VERSION 5.8 ;
BUSBITCHARS "[]" ;
DIVIDERCHAR "/" ;
UNITS
    DATABASE MICRONS 1000 ;
END UNITS

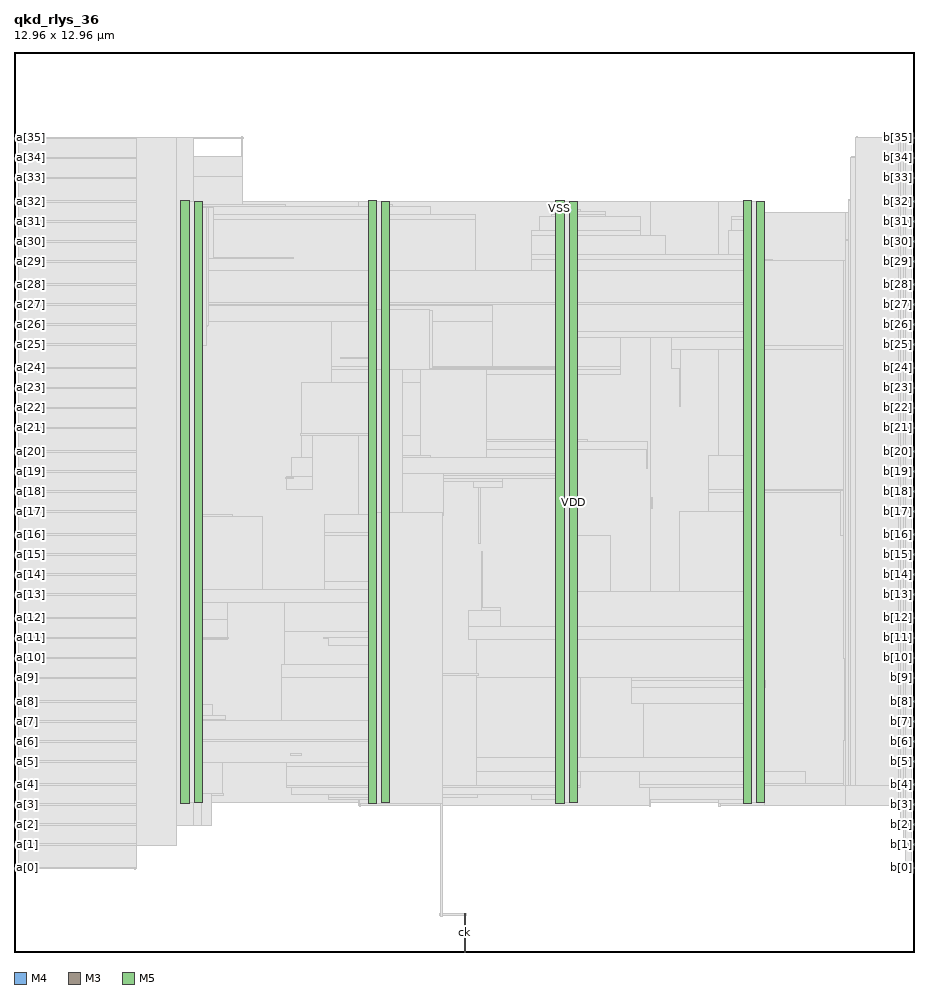
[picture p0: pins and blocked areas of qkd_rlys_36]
MACRO qkd_rlys_36
  FOREIGN qkd_rlys_36 0 0 ;
  CLASS BLOCK ;
  SIZE 12.96 BY 12.96 ;
  PIN a[0]
    DIRECTION INPUT ;
    USE SIGNAL ;
    PORT
      LAYER M4 ;
        RECT  0 1.2 0.084 1.224 ;
    END
  END a[0]
  PIN a[10]
    DIRECTION INPUT ;
    USE SIGNAL ;
    PORT
      LAYER M4 ;
        RECT  0 4.224 0.084 4.248 ;
    END
  END a[10]
  PIN a[11]
    DIRECTION INPUT ;
    USE SIGNAL ;
    PORT
      LAYER M4 ;
        RECT  0 4.512 0.084 4.536 ;
    END
  END a[11]
  PIN a[12]
    DIRECTION INPUT ;
    USE SIGNAL ;
    PORT
      LAYER M4 ;
        RECT  0 4.8 0.084 4.824 ;
    END
  END a[12]
  PIN a[13]
    DIRECTION INPUT ;
    USE SIGNAL ;
    PORT
      LAYER M4 ;
        RECT  0 5.136 0.084 5.16 ;
    END
  END a[13]
  PIN a[14]
    DIRECTION INPUT ;
    USE SIGNAL ;
    PORT
      LAYER M4 ;
        RECT  0 5.424 0.084 5.448 ;
    END
  END a[14]
  PIN a[15]
    DIRECTION INPUT ;
    USE SIGNAL ;
    PORT
      LAYER M4 ;
        RECT  0 5.712 0.084 5.736 ;
    END
  END a[15]
  PIN a[16]
    DIRECTION INPUT ;
    USE SIGNAL ;
    PORT
      LAYER M4 ;
        RECT  0 6 0.084 6.024 ;
    END
  END a[16]
  PIN a[17]
    DIRECTION INPUT ;
    USE SIGNAL ;
    PORT
      LAYER M4 ;
        RECT  0 6.336 0.084 6.36 ;
    END
  END a[17]
  PIN a[18]
    DIRECTION INPUT ;
    USE SIGNAL ;
    PORT
      LAYER M4 ;
        RECT  0 6.624 0.084 6.648 ;
    END
  END a[18]
  PIN a[19]
    DIRECTION INPUT ;
    USE SIGNAL ;
    PORT
      LAYER M4 ;
        RECT  0 6.912 0.084 6.936 ;
    END
  END a[19]
  PIN a[1]
    DIRECTION INPUT ;
    USE SIGNAL ;
    PORT
      LAYER M4 ;
        RECT  0 1.536 0.084 1.56 ;
    END
  END a[1]
  PIN a[20]
    DIRECTION INPUT ;
    USE SIGNAL ;
    PORT
      LAYER M4 ;
        RECT  0 7.2 0.084 7.224 ;
    END
  END a[20]
  PIN a[21]
    DIRECTION INPUT ;
    USE SIGNAL ;
    PORT
      LAYER M4 ;
        RECT  0 7.536 0.084 7.56 ;
    END
  END a[21]
  PIN a[22]
    DIRECTION INPUT ;
    USE SIGNAL ;
    PORT
      LAYER M4 ;
        RECT  0 7.824 0.084 7.848 ;
    END
  END a[22]
  PIN a[23]
    DIRECTION INPUT ;
    USE SIGNAL ;
    PORT
      LAYER M4 ;
        RECT  0 8.112 0.084 8.136 ;
    END
  END a[23]
  PIN a[24]
    DIRECTION INPUT ;
    USE SIGNAL ;
    PORT
      LAYER M4 ;
        RECT  0 8.4 0.084 8.424 ;
    END
  END a[24]
  PIN a[25]
    DIRECTION INPUT ;
    USE SIGNAL ;
    PORT
      LAYER M4 ;
        RECT  0 8.736 0.084 8.76 ;
    END
  END a[25]
  PIN a[26]
    DIRECTION INPUT ;
    USE SIGNAL ;
    PORT
      LAYER M4 ;
        RECT  0 9.024 0.084 9.048 ;
    END
  END a[26]
  PIN a[27]
    DIRECTION INPUT ;
    USE SIGNAL ;
    PORT
      LAYER M4 ;
        RECT  0 9.312 0.084 9.336 ;
    END
  END a[27]
  PIN a[28]
    DIRECTION INPUT ;
    USE SIGNAL ;
    PORT
      LAYER M4 ;
        RECT  0 9.6 0.084 9.624 ;
    END
  END a[28]
  PIN a[29]
    DIRECTION INPUT ;
    USE SIGNAL ;
    PORT
      LAYER M4 ;
        RECT  0 9.936 0.084 9.96 ;
    END
  END a[29]
  PIN a[2]
    DIRECTION INPUT ;
    USE SIGNAL ;
    PORT
      LAYER M4 ;
        RECT  0 1.824 0.084 1.848 ;
    END
  END a[2]
  PIN a[30]
    DIRECTION INPUT ;
    USE SIGNAL ;
    PORT
      LAYER M4 ;
        RECT  0 10.224 0.084 10.248 ;
    END
  END a[30]
  PIN a[31]
    DIRECTION INPUT ;
    USE SIGNAL ;
    PORT
      LAYER M4 ;
        RECT  0 10.512 0.084 10.536 ;
    END
  END a[31]
  PIN a[32]
    DIRECTION INPUT ;
    USE SIGNAL ;
    PORT
      LAYER M4 ;
        RECT  0 10.8 0.084 10.824 ;
    END
  END a[32]
  PIN a[33]
    DIRECTION INPUT ;
    USE SIGNAL ;
    PORT
      LAYER M4 ;
        RECT  0 11.136 0.084 11.16 ;
    END
  END a[33]
  PIN a[34]
    DIRECTION INPUT ;
    USE SIGNAL ;
    PORT
      LAYER M4 ;
        RECT  0 11.424 0.084 11.448 ;
    END
  END a[34]
  PIN a[35]
    DIRECTION INPUT ;
    USE SIGNAL ;
    PORT
      LAYER M4 ;
        RECT  0 11.712 0.084 11.736 ;
    END
  END a[35]
  PIN a[3]
    DIRECTION INPUT ;
    USE SIGNAL ;
    PORT
      LAYER M4 ;
        RECT  0 2.112 0.084 2.136 ;
    END
  END a[3]
  PIN a[4]
    DIRECTION INPUT ;
    USE SIGNAL ;
    PORT
      LAYER M4 ;
        RECT  0 2.4 0.084 2.424 ;
    END
  END a[4]
  PIN a[5]
    DIRECTION INPUT ;
    USE SIGNAL ;
    PORT
      LAYER M4 ;
        RECT  0 2.736 0.084 2.76 ;
    END
  END a[5]
  PIN a[6]
    DIRECTION INPUT ;
    USE SIGNAL ;
    PORT
      LAYER M4 ;
        RECT  0 3.024 0.084 3.048 ;
    END
  END a[6]
  PIN a[7]
    DIRECTION INPUT ;
    USE SIGNAL ;
    PORT
      LAYER M4 ;
        RECT  0 3.312 0.084 3.336 ;
    END
  END a[7]
  PIN a[8]
    DIRECTION INPUT ;
    USE SIGNAL ;
    PORT
      LAYER M4 ;
        RECT  0 3.6 0.084 3.624 ;
    END
  END a[8]
  PIN a[9]
    DIRECTION INPUT ;
    USE SIGNAL ;
    PORT
      LAYER M4 ;
        RECT  0 3.936 0.084 3.96 ;
    END
  END a[9]
  PIN b[0]
    DIRECTION OUTPUT ;
    USE SIGNAL ;
    PORT
      LAYER M4 ;
        RECT  12.876 1.2 12.96 1.224 ;
    END
  END b[0]
  PIN b[10]
    DIRECTION OUTPUT ;
    USE SIGNAL ;
    PORT
      LAYER M4 ;
        RECT  12.876 4.224 12.96 4.248 ;
    END
  END b[10]
  PIN b[11]
    DIRECTION OUTPUT ;
    USE SIGNAL ;
    PORT
      LAYER M4 ;
        RECT  12.876 4.512 12.96 4.536 ;
    END
  END b[11]
  PIN b[12]
    DIRECTION OUTPUT ;
    USE SIGNAL ;
    PORT
      LAYER M4 ;
        RECT  12.876 4.8 12.96 4.824 ;
    END
  END b[12]
  PIN b[13]
    DIRECTION OUTPUT ;
    USE SIGNAL ;
    PORT
      LAYER M4 ;
        RECT  12.876 5.136 12.96 5.16 ;
    END
  END b[13]
  PIN b[14]
    DIRECTION OUTPUT ;
    USE SIGNAL ;
    PORT
      LAYER M4 ;
        RECT  12.876 5.424 12.96 5.448 ;
    END
  END b[14]
  PIN b[15]
    DIRECTION OUTPUT ;
    USE SIGNAL ;
    PORT
      LAYER M4 ;
        RECT  12.876 5.712 12.96 5.736 ;
    END
  END b[15]
  PIN b[16]
    DIRECTION OUTPUT ;
    USE SIGNAL ;
    PORT
      LAYER M4 ;
        RECT  12.876 6 12.96 6.024 ;
    END
  END b[16]
  PIN b[17]
    DIRECTION OUTPUT ;
    USE SIGNAL ;
    PORT
      LAYER M4 ;
        RECT  12.876 6.336 12.96 6.36 ;
    END
  END b[17]
  PIN b[18]
    DIRECTION OUTPUT ;
    USE SIGNAL ;
    PORT
      LAYER M4 ;
        RECT  12.876 6.624 12.96 6.648 ;
    END
  END b[18]
  PIN b[19]
    DIRECTION OUTPUT ;
    USE SIGNAL ;
    PORT
      LAYER M4 ;
        RECT  12.876 6.912 12.96 6.936 ;
    END
  END b[19]
  PIN b[1]
    DIRECTION OUTPUT ;
    USE SIGNAL ;
    PORT
      LAYER M4 ;
        RECT  12.876 1.536 12.96 1.56 ;
    END
  END b[1]
  PIN b[20]
    DIRECTION OUTPUT ;
    USE SIGNAL ;
    PORT
      LAYER M4 ;
        RECT  12.876 7.2 12.96 7.224 ;
    END
  END b[20]
  PIN b[21]
    DIRECTION OUTPUT ;
    USE SIGNAL ;
    PORT
      LAYER M4 ;
        RECT  12.876 7.536 12.96 7.56 ;
    END
  END b[21]
  PIN b[22]
    DIRECTION OUTPUT ;
    USE SIGNAL ;
    PORT
      LAYER M4 ;
        RECT  12.876 7.824 12.96 7.848 ;
    END
  END b[22]
  PIN b[23]
    DIRECTION OUTPUT ;
    USE SIGNAL ;
    PORT
      LAYER M4 ;
        RECT  12.876 8.112 12.96 8.136 ;
    END
  END b[23]
  PIN b[24]
    DIRECTION OUTPUT ;
    USE SIGNAL ;
    PORT
      LAYER M4 ;
        RECT  12.876 8.4 12.96 8.424 ;
    END
  END b[24]
  PIN b[25]
    DIRECTION OUTPUT ;
    USE SIGNAL ;
    PORT
      LAYER M4 ;
        RECT  12.876 8.736 12.96 8.76 ;
    END
  END b[25]
  PIN b[26]
    DIRECTION OUTPUT ;
    USE SIGNAL ;
    PORT
      LAYER M4 ;
        RECT  12.876 9.024 12.96 9.048 ;
    END
  END b[26]
  PIN b[27]
    DIRECTION OUTPUT ;
    USE SIGNAL ;
    PORT
      LAYER M4 ;
        RECT  12.876 9.312 12.96 9.336 ;
    END
  END b[27]
  PIN b[28]
    DIRECTION OUTPUT ;
    USE SIGNAL ;
    PORT
      LAYER M4 ;
        RECT  12.876 9.6 12.96 9.624 ;
    END
  END b[28]
  PIN b[29]
    DIRECTION OUTPUT ;
    USE SIGNAL ;
    PORT
      LAYER M4 ;
        RECT  12.876 9.936 12.96 9.96 ;
    END
  END b[29]
  PIN b[2]
    DIRECTION OUTPUT ;
    USE SIGNAL ;
    PORT
      LAYER M4 ;
        RECT  12.876 1.824 12.96 1.848 ;
    END
  END b[2]
  PIN b[30]
    DIRECTION OUTPUT ;
    USE SIGNAL ;
    PORT
      LAYER M4 ;
        RECT  12.876 10.224 12.96 10.248 ;
    END
  END b[30]
  PIN b[31]
    DIRECTION OUTPUT ;
    USE SIGNAL ;
    PORT
      LAYER M4 ;
        RECT  12.876 10.512 12.96 10.536 ;
    END
  END b[31]
  PIN b[32]
    DIRECTION OUTPUT ;
    USE SIGNAL ;
    PORT
      LAYER M4 ;
        RECT  12.876 10.8 12.96 10.824 ;
    END
  END b[32]
  PIN b[33]
    DIRECTION OUTPUT ;
    USE SIGNAL ;
    PORT
      LAYER M4 ;
        RECT  12.876 11.136 12.96 11.16 ;
    END
  END b[33]
  PIN b[34]
    DIRECTION OUTPUT ;
    USE SIGNAL ;
    PORT
      LAYER M4 ;
        RECT  12.876 11.424 12.96 11.448 ;
    END
  END b[34]
  PIN b[35]
    DIRECTION OUTPUT ;
    USE SIGNAL ;
    PORT
      LAYER M4 ;
        RECT  12.876 11.712 12.96 11.736 ;
    END
  END b[35]
  PIN b[3]
    DIRECTION OUTPUT ;
    USE SIGNAL ;
    PORT
      LAYER M4 ;
        RECT  12.876 2.112 12.96 2.136 ;
    END
  END b[3]
  PIN b[4]
    DIRECTION OUTPUT ;
    USE SIGNAL ;
    PORT
      LAYER M4 ;
        RECT  12.876 2.4 12.96 2.424 ;
    END
  END b[4]
  PIN b[5]
    DIRECTION OUTPUT ;
    USE SIGNAL ;
    PORT
      LAYER M4 ;
        RECT  12.876 2.736 12.96 2.76 ;
    END
  END b[5]
  PIN b[6]
    DIRECTION OUTPUT ;
    USE SIGNAL ;
    PORT
      LAYER M4 ;
        RECT  12.876 3.024 12.96 3.048 ;
    END
  END b[6]
  PIN b[7]
    DIRECTION OUTPUT ;
    USE SIGNAL ;
    PORT
      LAYER M4 ;
        RECT  12.876 3.312 12.96 3.336 ;
    END
  END b[7]
  PIN b[8]
    DIRECTION OUTPUT ;
    USE SIGNAL ;
    PORT
      LAYER M4 ;
        RECT  12.876 3.6 12.96 3.624 ;
    END
  END b[8]
  PIN b[9]
    DIRECTION OUTPUT ;
    USE SIGNAL ;
    PORT
      LAYER M4 ;
        RECT  12.876 3.936 12.96 3.96 ;
    END
  END b[9]
  PIN ck
    DIRECTION INPUT ;
    USE SIGNAL ;
    PORT
      LAYER M3 ;
        RECT  6.48 0 6.498 0.038 ;
    END
    PORT
      LAYER M3 ;
        RECT  6.48 0.012 6.498 0.557 ;
    END
  END ck
  PIN VDD
    DIRECTION INOUT ;
    USE POWER ;
    PORT
      LAYER M5 ;
        RECT  10.692 2.151 10.812 10.809 ;
        RECT  7.992 2.151 8.112 10.809 ;
        RECT  5.292 2.151 5.412 10.809 ;
        RECT  2.592 2.151 2.712 10.809 ;
    END
  END VDD
  PIN VSS
    DIRECTION INOUT ;
    USE GROUND ;
    PORT
      LAYER M5 ;
        RECT  10.5 2.137 10.62 10.823 ;
        RECT  7.8 2.137 7.92 10.823 ;
        RECT  5.1 2.137 5.22 10.823 ;
        RECT  2.4 2.137 2.52 10.823 ;
    END
  END VSS
  # OT_OBS_CLOSED layer=M5 d_um=1.536 added=0
  OBS
    LAYER RVTN ;
     RECT  2.16 2.16 10.8 2.295 ;
     RECT  2.16 2.565 10.8 2.835 ;
     RECT  2.16 3.105 10.8 3.375 ;
     RECT  2.16 3.645 10.8 3.915 ;
     RECT  2.16 4.185 10.8 4.455 ;
     RECT  2.16 4.725 10.8 4.995 ;
     RECT  2.16 5.265 10.8 5.535 ;
     RECT  2.16 5.805 10.8 6.075 ;
     RECT  2.16 6.345 10.8 6.615 ;
     RECT  2.16 6.885 10.8 7.155 ;
     RECT  2.16 7.425 10.8 7.695 ;
     RECT  2.16 7.965 10.8 8.235 ;
     RECT  2.16 8.505 10.8 8.775 ;
     RECT  2.16 9.045 10.8 9.315 ;
     RECT  2.16 9.585 10.8 9.855 ;
     RECT  2.16 10.125 10.8 10.395 ;
     RECT  2.16 10.665 10.8 10.8 ;
    LAYER RVTP ;
     RECT  2.16 2.295 10.8 2.565 ;
     RECT  2.16 2.835 10.8 3.105 ;
     RECT  2.16 3.375 10.8 3.645 ;
     RECT  2.16 3.915 10.8 4.185 ;
     RECT  2.16 4.455 10.8 4.725 ;
     RECT  2.16 4.995 10.8 5.265 ;
     RECT  2.16 5.535 10.8 5.805 ;
     RECT  2.16 6.075 10.8 6.345 ;
     RECT  2.16 6.615 10.8 6.885 ;
     RECT  2.16 7.155 10.8 7.425 ;
     RECT  2.16 7.695 10.8 7.965 ;
     RECT  2.16 8.235 10.8 8.505 ;
     RECT  2.16 8.775 10.8 9.045 ;
     RECT  2.16 9.315 10.8 9.585 ;
     RECT  2.16 9.855 10.8 10.125 ;
     RECT  2.16 10.395 10.8 10.665 ;
    LAYER M1 ;
     RECT  2.16 2.151 10.8 10.809 ;
    LAYER M2 ;
     RECT  1.723 2.232 2.16 2.25 ;
     RECT  2.16 2.151 4.963 10.809 ;
     RECT  4.963 2.106 9.167 10.809 ;
     RECT  9.167 2.151 10.147 10.809 ;
     RECT  10.147 2.106 10.8 10.809 ;
     RECT  10.8 2.106 11.975 10.656 ;
     RECT  11.975 5.004 12.011 5.022 ;
     RECT  11.975 6.156 12.011 6.804 ;
     RECT  11.975 8.946 12.011 10.656 ;
     RECT  12.011 9.63 12.119 10.656 ;
     RECT  12.119 9.63 12.155 9.648 ;
     RECT  11.975 2.106 12.803 4.014 ;
     RECT  12.803 3.186 12.839 4.014 ;
     RECT  12.803 2.106 12.875 2.124 ;
     RECT  12.839 3.42 12.875 4.014 ;
     RECT  12.119 10.638 12.875 10.656 ;
    LAYER M3 ;
     RECT  1.728 1.195 1.746 1.531 ;
     RECT  12.852 1.195 12.87 1.531 ;
     RECT  1.728 1.531 2.322 1.819 ;
     RECT  12.816 1.531 12.87 1.819 ;
     RECT  12.78 1.819 12.87 2.107 ;
     RECT  4.968 2.101 4.986 2.143 ;
     RECT  10.152 2.101 10.17 2.143 ;
     RECT  4.968 2.143 5.205 2.191 ;
     RECT  7.815 2.143 7.905 2.191 ;
     RECT  9.144 2.101 9.162 2.191 ;
     RECT  10.152 2.143 10.605 2.191 ;
     RECT  4.536 2.191 6.03 2.227 ;
     RECT  1.728 1.819 2.826 2.251 ;
     RECT  1.728 2.251 3.006 2.255 ;
     RECT  4.536 2.227 6.678 2.263 ;
     RECT  7.452 2.191 7.905 2.263 ;
     RECT  0.108 2.107 0.126 2.285 ;
     RECT  3.996 2.263 7.905 2.371 ;
     RECT  9.144 2.191 10.605 2.371 ;
     RECT  3.924 2.371 8.154 2.399 ;
     RECT  12.744 2.107 12.87 2.399 ;
     RECT  9 2.371 10.605 2.413 ;
     RECT  11.376 2.395 11.394 2.413 ;
     RECT  9 2.413 11.394 2.597 ;
     RECT  6.66 2.399 8.154 2.605 ;
     RECT  9 2.597 10.797 2.605 ;
     RECT  3.924 2.399 5.742 2.669 ;
     RECT  12.78 2.399 12.87 2.669 ;
     RECT  2.304 2.255 3.006 2.731 ;
     RECT  3.924 2.669 5.562 2.731 ;
     RECT  6.66 2.605 10.797 2.795 ;
     RECT  2.304 2.731 5.562 3.029 ;
     RECT  2.304 3.029 5.454 3.065 ;
     RECT  2.304 3.065 5.397 3.335 ;
     RECT  2.304 3.335 3.042 3.344 ;
     RECT  2.34 3.344 3.042 3.407 ;
     RECT  11.952 3.019 11.97 3.451 ;
     RECT  2.34 3.407 2.862 3.569 ;
     RECT  9.072 2.795 10.797 3.577 ;
     RECT  11.952 3.451 12.006 3.629 ;
     RECT  8.892 3.577 10.797 3.811 ;
     RECT  12.816 2.669 12.87 3.839 ;
     RECT  8.892 3.811 10.818 3.911 ;
     RECT  3.852 3.335 5.397 3.955 ;
     RECT  6.66 2.795 8.154 3.955 ;
     RECT  8.892 3.911 10.797 3.955 ;
     RECT  12.852 3.839 12.87 4.019 ;
     RECT  3.852 3.955 5.742 4.145 ;
     RECT  6.66 3.955 10.797 4.495 ;
     RECT  2.34 3.569 2.697 4.507 ;
     RECT  3.888 4.145 5.742 4.621 ;
     RECT  6.552 4.495 10.797 4.685 ;
     RECT  2.34 4.507 3.078 4.795 ;
     RECT  6.552 4.685 7.002 4.919 ;
     RECT  6.732 4.919 7.002 4.955 ;
     RECT  11.952 3.629 11.97 4.999 ;
     RECT  2.304 4.795 3.078 5.035 ;
     RECT  3.888 4.621 5.778 5.035 ;
     RECT  11.952 4.999 12.006 5.165 ;
     RECT  7.815 4.685 10.797 5.189 ;
     RECT  2.304 5.035 5.778 5.225 ;
     RECT  4.464 5.225 5.778 5.341 ;
     RECT  6.732 4.955 6.75 5.765 ;
     RECT  11.952 5.165 11.97 5.995 ;
     RECT  4.464 5.341 5.922 5.999 ;
     RECT  7.815 5.189 8.586 5.999 ;
     RECT  4.464 5.999 5.706 6.035 ;
     RECT  11.916 5.995 11.97 6.151 ;
     RECT  2.304 5.225 3.582 6.269 ;
     RECT  2.304 6.269 3.15 6.305 ;
     RECT  4.464 6.035 5.418 6.305 ;
     RECT  9.576 5.189 10.797 6.341 ;
     RECT  9.18 6.385 9.198 6.539 ;
     RECT  10.008 6.341 10.797 6.613 ;
     RECT  11.916 6.151 12.006 6.613 ;
     RECT  10.008 6.613 12.006 6.653 ;
     RECT  6.696 5.881 6.714 6.691 ;
     RECT  5.115 6.305 5.418 6.781 ;
     RECT  6.624 6.691 7.038 6.781 ;
     RECT  5.115 6.781 7.038 6.817 ;
     RECT  7.815 5.999 8.097 6.817 ;
     RECT  3.924 6.655 4.302 6.845 ;
     RECT  11.952 6.653 12.006 6.941 ;
     RECT  3.996 6.845 4.302 7.115 ;
     RECT  5.115 6.817 8.097 7.115 ;
     RECT  5.115 7.115 5.994 7.151 ;
     RECT  10.008 6.653 10.797 7.151 ;
     RECT  6.804 7.115 8.097 7.231 ;
     RECT  9.108 6.961 9.126 7.231 ;
     RECT  6.804 7.231 9.126 7.349 ;
     RECT  6.804 7.349 8.262 7.385 ;
     RECT  4.14 7.115 4.302 7.435 ;
     RECT  5.115 7.151 5.85 7.435 ;
     RECT  2.304 6.305 2.697 8.195 ;
     RECT  4.14 7.435 5.85 8.195 ;
     RECT  6.804 7.385 8.097 8.311 ;
     RECT  4.572 8.195 5.85 8.395 ;
     RECT  6.804 8.311 8.73 8.395 ;
     RECT  9.576 7.861 9.594 8.401 ;
     RECT  4.572 8.395 8.73 8.429 ;
     RECT  9.468 8.401 9.594 8.671 ;
     RECT  10.515 7.151 10.797 8.671 ;
     RECT  11.952 6.941 11.97 8.671 ;
     RECT  2.415 8.195 2.697 8.731 ;
     RECT  7.815 8.429 8.73 8.851 ;
     RECT  9.468 8.671 11.97 8.851 ;
     RECT  7.815 8.851 11.97 8.941 ;
     RECT  2.415 8.731 2.754 9.004 ;
     RECT  2.415 9.004 2.79 9.085 ;
     RECT  4.572 8.429 6.894 9.085 ;
     RECT  2.415 9.085 6.894 9.307 ;
     RECT  2.304 9.307 6.894 9.319 ;
     RECT  7.815 8.941 12.006 9.319 ;
     RECT  2.304 9.319 12.006 9.347 ;
     RECT  11.988 9.347 12.006 9.625 ;
     RECT  2.304 9.347 10.926 9.815 ;
     RECT  7.452 9.815 10.926 9.965 ;
     RECT  7.452 9.965 10.797 10.049 ;
     RECT  11.988 9.625 12.15 10.253 ;
     RECT  7.452 10.049 9.378 10.319 ;
     RECT  7.452 10.319 9.018 10.391 ;
     RECT  10.296 10.049 10.797 10.391 ;
     RECT  12.024 10.253 12.15 10.507 ;
     RECT  2.304 9.815 6.642 10.541 ;
     RECT  10.332 10.391 10.797 10.547 ;
     RECT  7.56 10.391 9.018 10.589 ;
     RECT  10.332 10.547 10.605 10.589 ;
     RECT  2.34 10.541 6.642 10.625 ;
     RECT  7.74 10.589 8.514 10.625 ;
     RECT  7.815 10.625 8.514 10.661 ;
     RECT  12.024 10.507 12.87 10.661 ;
     RECT  7.815 10.661 8.154 10.697 ;
     RECT  2.34 10.625 5.994 10.733 ;
     RECT  2.34 10.733 3.906 10.769 ;
     RECT  5.115 10.733 5.454 10.769 ;
     RECT  5.115 10.769 5.205 10.817 ;
     RECT  7.815 10.697 7.905 10.817 ;
     RECT  10.515 10.589 10.605 10.817 ;
     RECT  0.108 10.699 0.126 10.829 ;
     RECT  12.024 10.661 12.15 10.829 ;
     RECT  2.34 10.769 3.294 11.165 ;
     RECT  2.556 11.165 3.294 11.453 ;
     RECT  12.06 10.829 12.15 11.453 ;
     RECT  3.276 11.453 3.294 11.741 ;
     RECT  12.132 11.453 12.15 11.741 ;
    LAYER M4 ;
     RECT  0.084 1.2 1.757 1.224 ;
     RECT  0.06 1.224 1.757 1.536 ;
     RECT  0.084 1.536 1.757 1.56 ;
     RECT  0.06 1.56 1.757 1.824 ;
     RECT  0.084 1.824 1.757 1.848 ;
     RECT  0.06 1.848 1.757 2.112 ;
     RECT  0.084 2.112 1.757 2.136 ;
     RECT  0.06 2.136 1.757 2.4 ;
     RECT  0.084 2.4 1.757 2.424 ;
     RECT  0.06 2.424 1.757 2.736 ;
     RECT  0.084 2.736 1.757 2.76 ;
     RECT  0.06 2.76 1.757 3.024 ;
     RECT  0.084 3.024 1.757 3.048 ;
     RECT  0.06 3.048 1.757 3.312 ;
     RECT  0.084 3.312 1.757 3.336 ;
     RECT  0.06 3.336 1.757 3.6 ;
     RECT  0.084 3.6 1.757 3.624 ;
     RECT  0.06 3.624 1.757 3.936 ;
     RECT  0.084 3.936 1.757 3.96 ;
     RECT  0.06 3.96 1.757 4.224 ;
     RECT  0.084 4.224 1.757 4.248 ;
     RECT  0.06 4.248 1.757 4.512 ;
     RECT  0.084 4.512 1.757 4.536 ;
     RECT  0.06 4.536 1.757 4.8 ;
     RECT  0.084 4.8 1.757 4.824 ;
     RECT  0.06 4.824 1.757 5.136 ;
     RECT  0.084 5.136 1.757 5.16 ;
     RECT  0.06 5.16 1.757 5.424 ;
     RECT  0.084 5.424 1.757 5.448 ;
     RECT  0.06 5.448 1.757 5.712 ;
     RECT  0.084 5.712 1.757 5.736 ;
     RECT  0.06 5.736 1.757 6 ;
     RECT  0.084 6 1.757 6.024 ;
     RECT  0.06 6.024 1.757 6.336 ;
     RECT  0.084 6.336 1.757 6.36 ;
     RECT  0.06 6.36 1.757 6.624 ;
     RECT  0.084 6.624 1.757 6.648 ;
     RECT  0.06 6.648 1.757 6.912 ;
     RECT  0.084 6.912 1.757 6.936 ;
     RECT  0.06 6.936 1.757 7.2 ;
     RECT  0.084 7.2 1.757 7.224 ;
     RECT  0.06 7.224 1.757 7.536 ;
     RECT  0.084 7.536 1.757 7.56 ;
     RECT  0.06 7.56 1.757 7.824 ;
     RECT  0.084 7.824 1.757 7.848 ;
     RECT  0.06 7.848 1.757 8.112 ;
     RECT  0.084 8.112 1.757 8.136 ;
     RECT  0.06 8.136 1.757 8.4 ;
     RECT  0.084 8.4 1.757 8.424 ;
     RECT  0.06 8.424 1.757 8.736 ;
     RECT  0.084 8.736 1.757 8.76 ;
     RECT  0.06 8.76 1.757 9.024 ;
     RECT  0.084 9.024 1.757 9.048 ;
     RECT  0.06 9.048 1.757 9.312 ;
     RECT  0.084 9.312 1.757 9.336 ;
     RECT  0.06 9.336 1.757 9.6 ;
     RECT  0.084 9.6 1.757 9.624 ;
     RECT  0.06 9.624 1.757 9.936 ;
     RECT  0.084 9.936 1.757 9.96 ;
     RECT  0.06 9.96 1.757 10.224 ;
     RECT  0.084 10.224 1.757 10.248 ;
     RECT  0.06 10.248 1.757 10.512 ;
     RECT  0.084 10.512 1.757 10.536 ;
     RECT  0.06 10.536 1.757 10.8 ;
     RECT  0.084 10.8 1.757 10.824 ;
     RECT  0.06 10.824 1.757 11.136 ;
     RECT  0.084 11.136 1.757 11.16 ;
     RECT  0.06 11.16 1.757 11.424 ;
     RECT  0.084 11.424 1.757 11.448 ;
     RECT  0.06 11.448 1.757 11.712 ;
     RECT  0.084 11.712 1.757 11.736 ;
     RECT  1.757 1.536 2.333 11.736 ;
     RECT  2.333 1.824 2.585 11.736 ;
     RECT  2.585 1.824 2.704 10.728 ;
     RECT  2.704 8.736 2.765 10.728 ;
     RECT  2.765 9.024 2.801 10.728 ;
     RECT  2.704 1.824 2.837 2.28 ;
     RECT  2.801 9.984 2.873 10.728 ;
     RECT  2.837 2.256 3.017 2.28 ;
     RECT  2.704 4.512 3.089 4.536 ;
     RECT  2.585 11.712 3.305 11.736 ;
     RECT  3.913 6.816 4.025 6.84 ;
     RECT  2.873 9.984 4.025 10.008 ;
     RECT  3.985 2.832 4.133 2.856 ;
     RECT  4.453 4.512 4.525 4.536 ;
     RECT  4.525 4.416 5.108 4.536 ;
     RECT  4.129 7.44 5.108 7.464 ;
     RECT  4.705 8.544 5.108 8.568 ;
     RECT  5.108 2.148 5.212 10.812 ;
     RECT  5.212 2.418 5.404 10.542 ;
     RECT  5.404 3.984 5.609 5.112 ;
     RECT  5.404 8.4 6.028 9.24 ;
     RECT  5.404 6.288 6.179 6.888 ;
     RECT  6.133 0.528 6.509 0.552 ;
     RECT  5.609 3.984 6.689 4.008 ;
     RECT  6.179 6.864 7.808 6.888 ;
     RECT  6.028 8.4 7.808 8.424 ;
     RECT  7.808 2.148 7.912 10.812 ;
     RECT  7.912 2.418 8.104 10.542 ;
     RECT  10.508 2.148 10.612 10.812 ;
     RECT  10.612 2.4 10.804 10.542 ;
     RECT  10.804 6.624 11.905 6.648 ;
     RECT  10.804 2.4 11.941 2.424 ;
     RECT  11.905 6 11.941 6.648 ;
     RECT  10.804 8.736 11.941 9.96 ;
     RECT  11.941 2.4 11.977 3.048 ;
     RECT  11.941 4.224 11.977 9.96 ;
     RECT  11.977 2.4 12.013 10.248 ;
     RECT  12.013 2.4 12.049 10.824 ;
     RECT  12.049 2.4 12.121 11.448 ;
     RECT  12.121 2.4 12.733 11.736 ;
     RECT  12.733 2.112 12.769 11.736 ;
     RECT  12.769 1.824 12.805 11.736 ;
     RECT  12.805 1.536 12.841 11.736 ;
     RECT  12.841 1.2 12.876 1.224 ;
     RECT  12.841 1.224 12.924 1.536 ;
     RECT  12.841 1.536 12.876 1.56 ;
     RECT  12.841 1.56 12.924 1.824 ;
     RECT  12.841 1.824 12.876 1.848 ;
     RECT  12.841 1.848 12.924 2.112 ;
     RECT  12.841 2.112 12.876 2.136 ;
     RECT  12.841 2.136 12.924 2.4 ;
     RECT  12.841 2.4 12.876 2.424 ;
     RECT  12.841 2.424 12.924 2.736 ;
     RECT  12.841 2.736 12.876 2.76 ;
     RECT  12.841 2.76 12.924 3.024 ;
     RECT  12.841 3.024 12.876 3.048 ;
     RECT  12.841 3.048 12.924 3.312 ;
     RECT  12.841 3.312 12.876 3.336 ;
     RECT  12.841 3.336 12.924 3.6 ;
     RECT  12.841 3.6 12.876 3.624 ;
     RECT  12.841 3.624 12.924 3.936 ;
     RECT  12.841 3.936 12.876 3.96 ;
     RECT  12.841 3.96 12.924 4.224 ;
     RECT  12.841 4.224 12.876 4.248 ;
     RECT  12.841 4.248 12.924 4.512 ;
     RECT  12.841 4.512 12.876 4.536 ;
     RECT  12.841 4.536 12.924 4.8 ;
     RECT  12.841 4.8 12.876 4.824 ;
     RECT  12.841 4.824 12.924 5.136 ;
     RECT  12.841 5.136 12.876 5.16 ;
     RECT  12.841 5.16 12.924 5.424 ;
     RECT  12.841 5.424 12.876 5.448 ;
     RECT  12.841 5.448 12.924 5.712 ;
     RECT  12.841 5.712 12.876 5.736 ;
     RECT  12.841 5.736 12.924 6 ;
     RECT  12.841 6 12.876 6.024 ;
     RECT  12.841 6.024 12.924 6.336 ;
     RECT  12.841 6.336 12.876 6.36 ;
     RECT  12.841 6.36 12.924 6.624 ;
     RECT  12.841 6.624 12.876 6.648 ;
     RECT  12.841 6.648 12.924 6.912 ;
     RECT  12.841 6.912 12.876 6.936 ;
     RECT  12.841 6.936 12.924 7.2 ;
     RECT  12.841 7.2 12.876 7.224 ;
     RECT  12.841 7.224 12.924 7.536 ;
     RECT  12.841 7.536 12.876 7.56 ;
     RECT  12.841 7.56 12.924 7.824 ;
     RECT  12.841 7.824 12.876 7.848 ;
     RECT  12.841 7.848 12.924 8.112 ;
     RECT  12.841 8.112 12.876 8.136 ;
     RECT  12.841 8.136 12.924 8.4 ;
     RECT  12.841 8.4 12.876 8.424 ;
     RECT  12.841 8.424 12.924 8.736 ;
     RECT  12.841 8.736 12.876 8.76 ;
     RECT  12.841 8.76 12.924 9.024 ;
     RECT  12.841 9.024 12.876 9.048 ;
     RECT  12.841 9.048 12.924 9.312 ;
     RECT  12.841 9.312 12.876 9.336 ;
     RECT  12.841 9.336 12.924 9.6 ;
     RECT  12.841 9.6 12.876 9.624 ;
     RECT  12.841 9.624 12.924 9.936 ;
     RECT  12.841 9.936 12.876 9.96 ;
     RECT  12.841 9.96 12.924 10.224 ;
     RECT  12.841 10.224 12.876 10.248 ;
     RECT  12.841 10.248 12.924 10.512 ;
     RECT  12.841 10.512 12.876 10.536 ;
     RECT  12.841 10.536 12.924 10.8 ;
     RECT  12.841 10.8 12.876 10.824 ;
     RECT  12.841 10.824 12.924 11.136 ;
     RECT  12.841 11.136 12.876 11.16 ;
     RECT  12.841 11.16 12.924 11.424 ;
     RECT  12.841 11.424 12.876 11.448 ;
     RECT  12.841 11.448 12.924 11.712 ;
     RECT  12.841 11.712 12.876 11.736 ;
    LAYER M5 ;
     RECT  6.144 0.517 6.168 2.137 ;
     RECT  2.4 2.137 2.52 2.151 ;
     RECT  7.8 2.137 7.92 2.151 ;
     RECT  10.5 2.137 10.62 2.151 ;
     RECT  5.1 2.137 6.168 6.323 ;
     RECT  5.1 6.323 5.592 8.389 ;
     RECT  5.1 8.389 5.976 9.251 ;
     RECT  2.4 2.151 2.712 10.809 ;
     RECT  5.1 9.251 5.412 10.809 ;
     RECT  7.8 2.151 8.112 10.809 ;
     RECT  10.5 2.151 10.812 10.809 ;
     RECT  2.4 10.809 2.52 10.823 ;
     RECT  5.1 10.809 5.22 10.823 ;
     RECT  7.8 10.809 7.92 10.823 ;
     RECT  10.5 10.809 10.62 10.823 ;
  END
END qkd_rlys_36
END LIBRARY
